VERSION 5.8 ;
BUSBITCHARS "[]" ;
DIVIDERCHAR "/" ;
UNITS
 DATABASE MICRONS 2000 ;
END UNITS
LAYER M1
 TYPE ROUTING ;
 DIRECTION HORIZONTAL ;
 PITCH 0.2 ;
 WIDTH 0.1 ;
 SPACING 0.1 ;
END M1
SITE CoreSite
 CLASS CORE ;
 SYMMETRY X Y ;
 SIZE 1 BY 2 ;
END CoreSite
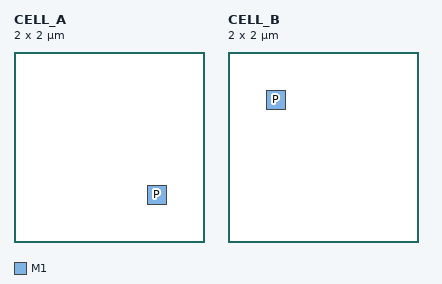
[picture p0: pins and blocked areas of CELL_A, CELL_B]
MACRO CELL_A
 CLASS CORE ;
 ORIGIN 0 0 ;
 SIZE 2 BY 2 ;
 SYMMETRY X Y ;
 SITE CoreSite ;
 PIN P
  DIRECTION INOUT ;
  PORT
   LAYER M1 ;
   RECT 1.4 0.4 1.6 0.6 ;
  END
 END P
END CELL_A
MACRO CELL_B
 CLASS CORE ;
 ORIGIN 0 0 ;
 SIZE 2 BY 2 ;
 SYMMETRY X Y ;
 SITE CoreSite ;
 PIN P
  DIRECTION INOUT ;
  PORT
   LAYER M1 ;
   RECT 0.4 1.4 0.6 1.6 ;
  END
 END P
END CELL_B
END LIBRARY
